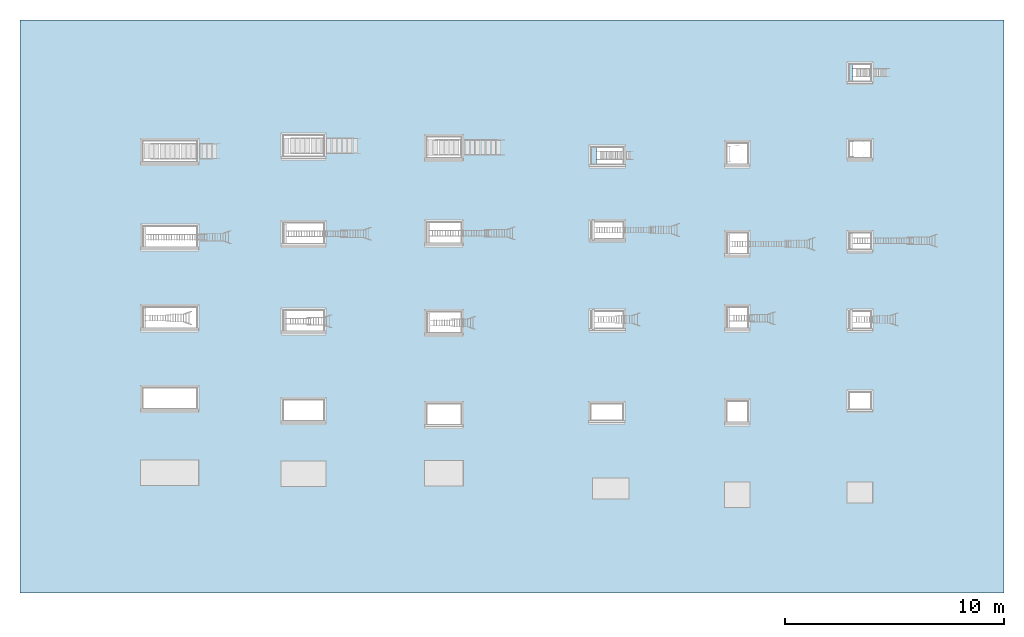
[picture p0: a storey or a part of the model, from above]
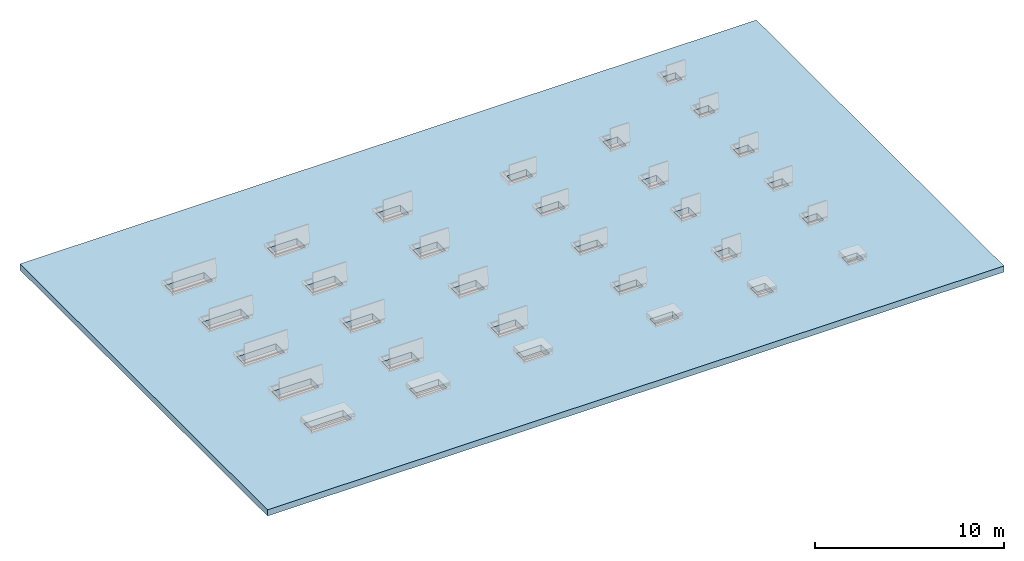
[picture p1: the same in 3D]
Properties of the parts of a building model (IFC2X3)

# File
Description: ViewDefinition [CoordinationView_V2.0]
File name: 0001
Time: 2017-12-15T08:57:58
Written by: The EXPRESS Data Manager Version 5.02.0100.07 : 28 Aug 2013
Made in: 20150220_1215(x64) - Exporter 16.6.0.0 - Alternate UI 16.6.0.0
Comment: STEP Physical File produced by: The EXPRESS Data Manager Version 5.02.0100.07 : 28 Aug 2013 * Module: EDMstepFileFactory/EDMstandAlone * Creation date: Fri Dec 15 08:57:58 2017 * Host: WINDOWS-V973HOM * Database: C:\Users\FELIXD~1\AppData\Local\Temp\{FE9802D2-C6F7-4746-8510-01C7067CA951}\ifc * Database version: 5507 * Database creation date: Fri Dec 15 08:57:52 2017 * Schema: IFC2X3 * Model: DataRepository.ifc * Model creation date: Fri Dec 15 08:57:52 2017 * Header model: DataRepository.ifc_HeaderModel * Header model creation date: Fri Dec 15 08:57:52 2017 * EDMuser: sdai-user * EDMgroup: sdai-group * License ID and type: 5605 : Permanent license. Expiry date: * EDMstepFileFactory options: 020000

# IfcProject, 0001
LongName: Project Name; Phase: Project Status

# IfcSite, Default
RefLatitude: 42, 21, 30, 344238; RefLongitude: -71, -3, -35, -194702; RefElevation: 0 mm

# IfcBuilding
Pset_BuildingCommon - NumberOfStoreys: 1

# IfcBuildingStorey, Level 2
LongName: Level 2; Elevation: 4000 mm

# IfcBuildingElementProxy: 1400 x 700 (2)
In: Level 2
Type - Classification: 37.2 (Uniformat)
Pset_BuildingElementProxyCommon - Reference: 1400 x 700
Pset_ManufacturerTypeInformation - Manufacturer: Staka Bouwproducten B.V.
Name (3_Topaccess_dakluik_1400x700_Staka:1400 x 700:...)
2426202
2426482

# IfcBuildingElementProxy: 1400 x 700 2part Stair, 3_Topaccess_dakluik_1400x700_Staka:1400 x 700 2part Stair:340159
In: Level 2
Type - Classification: 37.2 (Uniformat)
Pset_BuildingElementProxyCommon - Reference: 1400 x 700 2part Stair
Pset_ManufacturerTypeInformation - Manufacturer: Staka Bouwproducten B.V.

# IfcBuildingElementProxy: 1400 x 700 3part Stair, 3_Topaccess_dakluik_1400x700_Staka:1400 x 700 3part Stair:2426210
In: Level 2
Type - Classification: 37.2 (Uniformat)
Pset_BuildingElementProxyCommon - Reference: 1400 x 700 3part Stair
Pset_ManufacturerTypeInformation - Manufacturer: Staka Bouwproducten B.V.

# IfcBuildingElementProxy: 1400x 700 Scissor stair, 3_Topaccess_dakluik_1400x700_Staka:1400x 700 Scissor stair:2426218
In: Level 2
Type - Classification: 37.2 (Uniformat); Material: Analytical Floor Surface
Pset_BuildingElementProxyCommon - Reference: 1400x 700 Scissor stair
Pset_ManufacturerTypeInformation - Manufacturer: Staka Bouwproducten B.V.

# IfcBuildingElementProxy: 1500 x 900 (2)
In: Level 2
Type - Classification: 37.2 (Uniformat)
Pset_BuildingElementProxyCommon - Reference: 1500 x 900
Pset_ManufacturerTypeInformation - Manufacturer: Staka Bouwproducten B.V.
Name (4_Topaccess_dakluik_1500x900_Staka:1500 x 900:...)
2426244
2426466

# IfcBuildingElementProxy: 1500 x 900 2part Stair, 4_Topaccess_dakluik_1500x900_Staka:1500 x 900 2part Stair:2097633
In: Level 2
Type - Classification: 37.2 (Uniformat)
Pset_BuildingElementProxyCommon - Reference: 1500 x 900 2part Stair
Pset_ManufacturerTypeInformation - Manufacturer: Staka Bouwproducten B.V.

# IfcBuildingElementProxy: 1500 x 900 3part Stair, 4_Topaccess_dakluik_1500x900_Staka:1500 x 900 3part Stair:2426253
In: Level 2
Type - Classification: 37.2 (Uniformat)
Pset_BuildingElementProxyCommon - Reference: 1500 x 900 3part Stair
Pset_ManufacturerTypeInformation - Manufacturer: Staka Bouwproducten B.V.

# IfcBuildingElementProxy: 1500 x 900 Solid Stair, 4_Topaccess_dakluik_1500x900_Staka:1500 x 900 Solid Stair:2426262
In: Level 2
Type - Classification: 37.2 (Uniformat); Material: Analytical Floor Surface
Pset_BuildingElementProxyCommon - Reference: 1500 x 900 Solid Stair
Pset_ManufacturerTypeInformation - Manufacturer: Staka Bouwproducten B.V.

# IfcBuildingElementProxy: 1800 x 900 (2)
In: Level 2
Type - Classification: 37.2 (Uniformat)
Pset_BuildingElementProxyCommon - Reference: 1800 x 900
Pset_ManufacturerTypeInformation - Manufacturer: Staka Bouwproducten B.V.
Name (4_Topaccess_dakluik_1800x900_Staka:1800 x 900:...)
2426285
2426441

# IfcBuildingElementProxy: 1800 x 900 2part Stair, 4_Topaccess_dakluik_1800x900_Staka:1800 x 900 2part Stair:2111403
In: Level 2
Type - Classification: 37.2 (Uniformat)
Pset_BuildingElementProxyCommon - Reference: 1800 x 900 2part Stair
Pset_ManufacturerTypeInformation - Manufacturer: Staka Bouwproducten B.V.

# IfcBuildingElementProxy: 1800 x 900 3part Stair, 4_Topaccess_dakluik_1800x900_Staka:1800 x 900 3part Stair:2426294
In: Level 2
Type - Classification: 37.2 (Uniformat)
Pset_BuildingElementProxyCommon - Reference: 1800 x 900 3part Stair
Pset_ManufacturerTypeInformation - Manufacturer: Staka Bouwproducten B.V.

# IfcBuildingElementProxy: 1800 x 900 Solid Stair, 4_Topaccess_dakluik_1800x900_Staka:1800 x 900 Solid Stair:2426303
In: Level 2
Type - Classification: 37.2 (Uniformat); Material: Analytical Floor Surface
Pset_BuildingElementProxyCommon - Reference: 1800 x 900 Solid Stair
Pset_ManufacturerTypeInformation - Manufacturer: Staka Bouwproducten B.V.

# IfcBuildingElementProxy: 2400 x 900 (2)
In: Level 2
Type - Classification: 37.2 (Uniformat)
Pset_BuildingElementProxyCommon - Reference: 2400 x 900
Pset_ManufacturerTypeInformation - Manufacturer: Staka Bouwproducten B.V.
Name (5_Topaccess_dakluik_2400x900_Staka:2400 x 900:...)
2426326
2426423

# IfcBuildingElementProxy: 2400 x 900 2part Stair, 5_Topaccess_dakluik_2400x900_Staka:2400 x 900 2part Stair:422893
In: Level 2
Type - Classification: 37.2 (Uniformat)
Pset_BuildingElementProxyCommon - Reference: 2400 x 900 2part Stair
Pset_ManufacturerTypeInformation - Manufacturer: Staka Bouwproducten B.V.

# IfcBuildingElementProxy: 2400 x 900 3part Stair, 5_Topaccess_dakluik_2400x900_Staka:2400 x 900 3part Stair:2426334
In: Level 2
Type - Classification: 37.2 (Uniformat)
Pset_BuildingElementProxyCommon - Reference: 2400 x 900 3part Stair
Pset_ManufacturerTypeInformation - Manufacturer: Staka Bouwproducten B.V.

# IfcBuildingElementProxy: 2400 x 900 Solid Stair, 5_Topaccess_dakluik_2400x900_Staka:2400 x 900 Solid Stair:2426342
In: Level 2
Type - Classification: 37.2 (Uniformat); Material: Analytical Floor Surface
Pset_BuildingElementProxyCommon - Reference: 2400 x 900 Solid Stair
Pset_ManufacturerTypeInformation - Manufacturer: Staka Bouwproducten B.V.

# IfcBuildingElementProxy: 900 x 700 (2)
In: Level 2
Type - Classification: 37.2 (Uniformat)
Pset_BuildingElementProxyCommon - Reference: 900 x 700
Pset_ManufacturerTypeInformation - Manufacturer: Staka Bouwproductyen B.V.
Name (1_Topaccess_dakluik_900x700_Staka:900 x 700:...)
2426096
2426510

# IfcBuildingElementProxy: 900 x 700 2part Stair, 1_Topaccess_dakluik_900x700_Staka:900 x 700 2part Stair:422929
In: Level 2
Type - Classification: 37.2 (Uniformat)
Pset_BuildingElementProxyCommon - Reference: 900 x 700 2part Stair
Pset_ManufacturerTypeInformation - Manufacturer: Staka Bouwproductyen B.V.

# IfcBuildingElementProxy: 900 x 700 3part Stair, 1_Topaccess_dakluik_900x700_Staka:900 x 700 3part Stair:2426104
In: Level 2
Type - Classification: 37.2 (Uniformat)
Pset_BuildingElementProxyCommon - Reference: 900 x 700 3part Stair
Pset_ManufacturerTypeInformation - Manufacturer: Staka Bouwproductyen B.V.

# IfcBuildingElementProxy: 900 x 700 Cage ladder, 1_Topaccess_dakluik_900x700_Staka:900 x 700 Cage ladder:2426112
In: Level 2
Type - Classification: 37.2 (Uniformat); Material: Analytical Floor Surface
Pset_BuildingElementProxyCommon - Reference: 900 x 700 Cage ladder
Pset_ManufacturerTypeInformation - Manufacturer: Staka Bouwproductyen B.V.

# IfcBuildingElementProxy: 900 x 700 Scissor stair, 1_Topaccess_dakluik_900x700_Staka:900 x 700 Scissor stair:2426120
In: Level 2
Type - Classification: 37.2 (Uniformat); Material: Analytical Floor Surface
Pset_BuildingElementProxyCommon - Reference: 900 x 700 Scissor stair
Pset_ManufacturerTypeInformation - Manufacturer: Staka Bouwproductyen B.V.

# IfcBuildingElementProxy: 900 x 900 (2)
In: Level 2
Type - Classification: 37.2 (Uniformat)
Pset_BuildingElementProxyCommon - Reference: 900 x 900
Pset_ManufacturerTypeInformation - Manufacturer: Staka Bouwproducten B.V.
Name (2_Topaccess_dakluik_900x900_Staka:900 x 900:...)
2426163
2426496

# IfcBuildingElementProxy: 900 x 900 2part Stair, 2_Topaccess_dakluik_900x900_Staka:900 x 900 2part Stair:422911
In: Level 2
Type - Classification: 37.2 (Uniformat)
Pset_BuildingElementProxyCommon - Reference: 900 x 900 2part Stair
Pset_ManufacturerTypeInformation - Manufacturer: Staka Bouwproducten B.V.

# IfcBuildingElementProxy: 900 x 900 3part Stair, 2_Topaccess_dakluik_900x900_Staka:900 x 900 3part Stair:2426171
In: Level 2
Type - Classification: 37.2 (Uniformat)
Pset_BuildingElementProxyCommon - Reference: 900 x 900 3part Stair
Pset_ManufacturerTypeInformation - Manufacturer: Staka Bouwproducten B.V.

# IfcBuildingElementProxy: 900 x 900 Cage ladder, 2_Topaccess_dakluik_900x900_Staka:900 x 900 Cage ladder:2426179
In: Level 2
Type - Classification: 37.2 (Uniformat); Material: Analytical Floor Surface
Pset_BuildingElementProxyCommon - Reference: 900 x 900 Cage ladder
Pset_ManufacturerTypeInformation - Manufacturer: Staka Bouwproducten B.V.

# IfcBuildingElementProxy: 9_Topaccess_Trap_2delige1 (6)
In: Level 2
Pset_BuildingElementProxyCommon - Reference: 9_Topaccess_Trap_2delige1
Name (9_Topaccess_Trap_2delige1:9_Topaccess_Trap_2delige1:...)
2176336
2426145
2426188
2426226
2426313
2426351

# IfcBuildingElementProxy: 9_Topaccess_Trap_3delige1 (6)
In: Level 2
Pset_BuildingElementProxyCommon - Reference: 9_Topaccess_Trap_3delige1
Name (9_Topaccess_Trap_3delige1:9_Topaccess_Trap_3delige1:...)
2426149
2426191
2426229
2426272
2426295
2426353

# IfcRoof: Basic Roof:Generic - 400mm:335, Basic Roof:Generic - 400mm:308818
In: Level 2
Pset_RoofCommon - Reference: Generic - 400mm; IsExternal: yes; TotalArea: 1140.84 m2; ProjectedArea: 1179 m2

# IfcSlab: Basic Roof:Generic - 400mm:335, Basic Roof:Generic - 400mm:308818:1
In: Level 2
PredefinedType: ROOF; Material: Default Roof; Default Roof 400 mm
Pset_SlabCommon - Reference: Generic - 400mm; IsExternal: yes; PitchAngle: 0 deg
